(* Logix 5000 project; controller MyControlLogix 1756-L63 rev 13.1; software revision 13.04; part 2 of 4 *)
(* tags used below, declared in another part *)
   AFC56 : AFC;
(* MainProgram, continued *)

ROUTINE MainRoutine   (* ladder *)
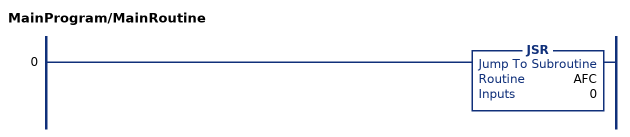
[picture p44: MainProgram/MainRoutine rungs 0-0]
   0: JSR(AFC,0);
END_ROUTINE

ROUTINE ModbusGateway_Block   (* ladder *)
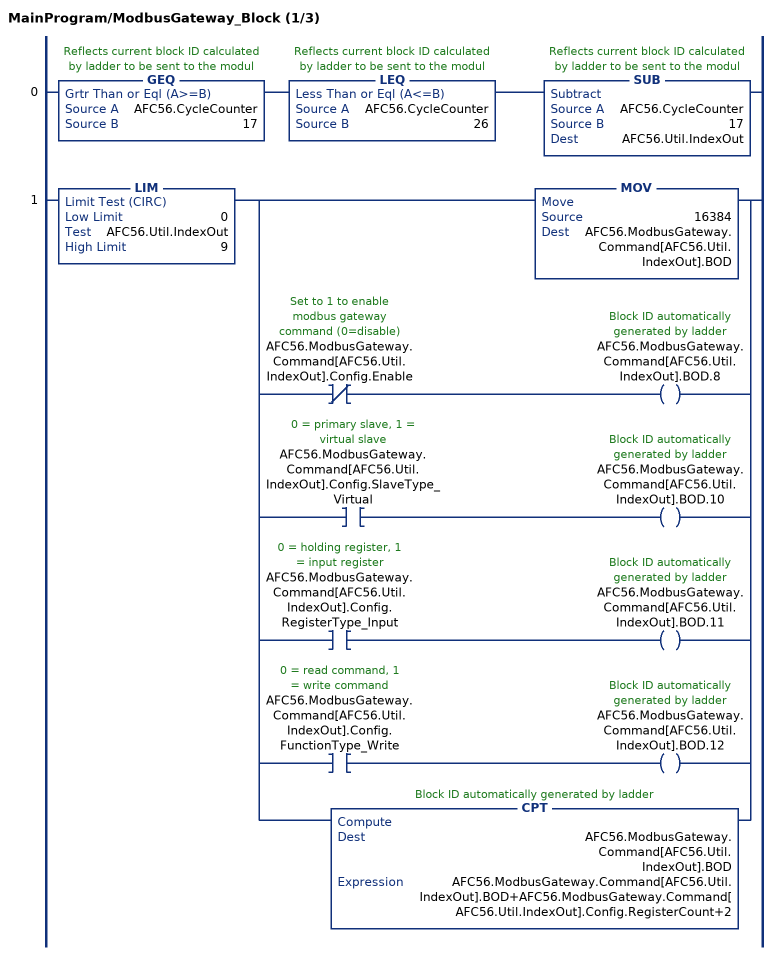
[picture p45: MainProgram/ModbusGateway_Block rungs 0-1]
   0: GEQ(AFC56.CycleCounter,17)LEQ(AFC56.CycleCounter,26)SUB(AFC56.CycleCounter,17,AFC56.Util.IndexOut);
   1: LIM(0,AFC56.Util.IndexOut,9)[MOV(16384,AFC56.ModbusGateway.Command[AFC56.Util.IndexOut].BOD) ,XIO(AFC56.ModbusGateway.Command[AFC56.Util.IndexOut].Config.Enable) OTE(AFC56.ModbusGateway.Command[AFC56.Util.IndexOut].BOD.8) ,XIC(AFC56.ModbusGateway.Command[AFC56.Util.IndexOut].Config.SlaveType_Virtual) OTE(AFC56.ModbusGateway.Command[AFC56.Util.IndexOut].BOD.10) ,XIC(AFC56.ModbusGateway.Command[AFC56.Util.IndexOut].Config.RegisterType_Input) OTE(AFC56.ModbusGateway.Command[AFC56.Util.IndexOut].BOD.11) ,XIC(AFC56.ModbusGateway.Command[AFC56.Util.IndexOut].Config.FunctionType_Write) OTE(AFC56.ModbusGateway.Command[AFC56.Util.IndexOut].BOD.12) ,CPT(AFC56.ModbusGateway.Command[AFC56.Util.IndexOut].BOD,AFC56.ModbusGateway.Command[AFC56.Util.IndexOut].BOD+AFC56.ModbusGateway.Command[AFC56.Util.IndexOut].Config.RegisterCount+2) ];
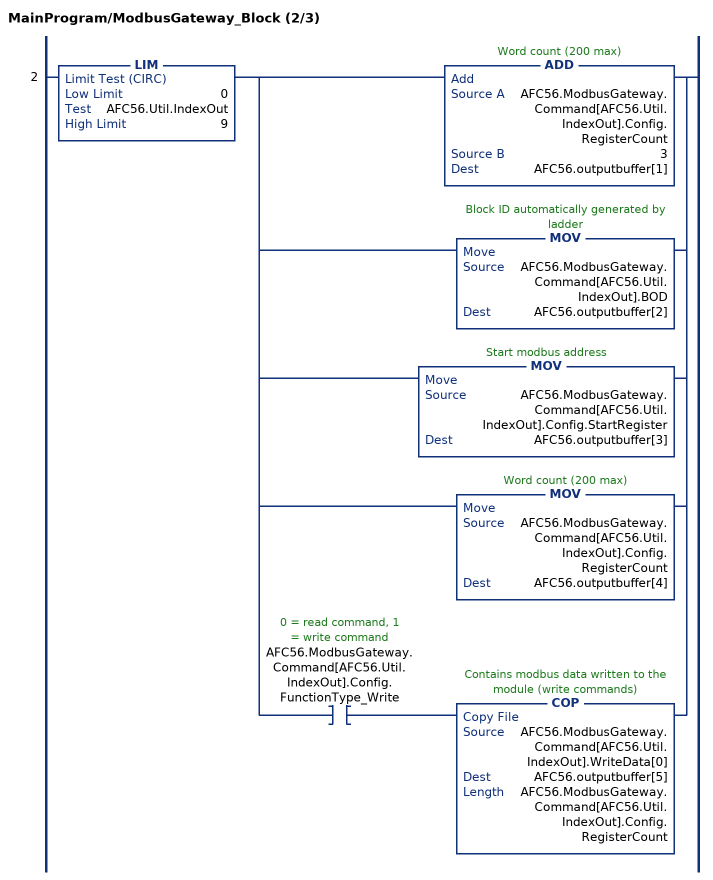
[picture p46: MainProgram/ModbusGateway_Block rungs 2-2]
   2: LIM(0,AFC56.Util.IndexOut,9)[ADD(AFC56.ModbusGateway.Command[AFC56.Util.IndexOut].Config.RegisterCount,3,AFC56.outputbuffer[1]) ,MOV(AFC56.ModbusGateway.Command[AFC56.Util.IndexOut].BOD,AFC56.outputbuffer[2]) ,MOV(AFC56.ModbusGateway.Command[AFC56.Util.IndexOut].Config.StartRegister,AFC56.outputbuffer[3]) ,MOV(AFC56.ModbusGateway.Command[AFC56.Util.IndexOut].Config.RegisterCount,AFC56.outputbuffer[4]) ,XIC(AFC56.ModbusGateway.Command[AFC56.Util.IndexOut].Config.FunctionType_Write) COP(AFC56.ModbusGateway.Command[AFC56.Util.IndexOut].WriteData[0],AFC56.outputbuffer[5],AFC56.ModbusGateway.Command[AFC56.Util.IndexOut].Config.RegisterCount) ];
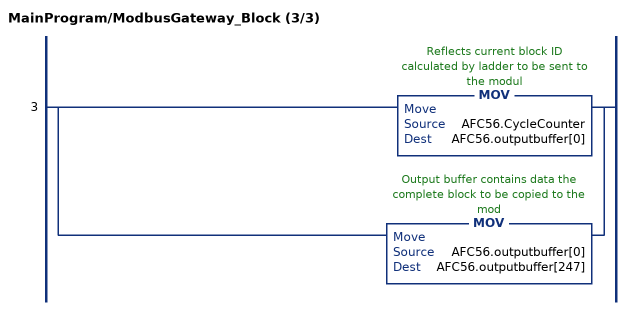
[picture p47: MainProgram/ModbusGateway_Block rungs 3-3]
   3: [MOV(AFC56.CycleCounter,AFC56.outputbuffer[0]) ,MOV(AFC56.outputbuffer[0],AFC56.outputbuffer[247]) ];
END_ROUTINE

ROUTINE ModbusMaster_Block   (* ladder *)
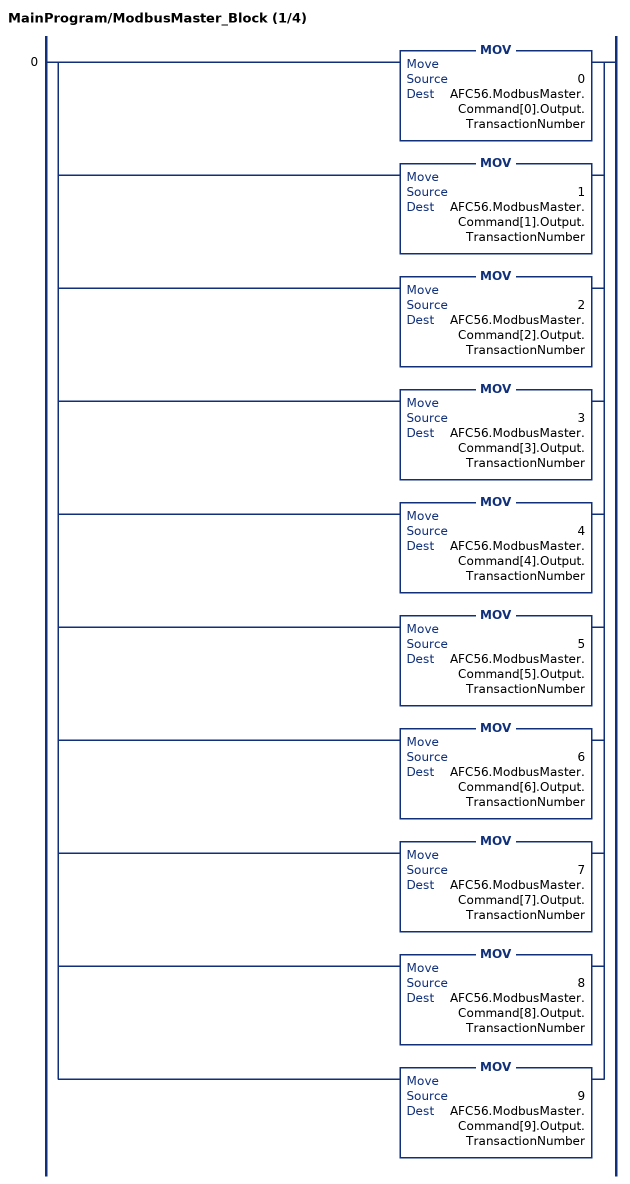
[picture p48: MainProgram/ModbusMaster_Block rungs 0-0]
   0: [MOV(0,AFC56.ModbusMaster.Command[0].Output.TransactionNumber) ,MOV(1,AFC56.ModbusMaster.Command[1].Output.TransactionNumber) ,MOV(2,AFC56.ModbusMaster.Command[2].Output.TransactionNumber) ,MOV(3,AFC56.ModbusMaster.Command[3].Output.TransactionNumber) ,MOV(4,AFC56.ModbusMaster.Command[4].Output.TransactionNumber) ,MOV(5,AFC56.ModbusMaster.Command[5].Output.TransactionNumber) ,MOV(6,AFC56.ModbusMaster.Command[6].Output.TransactionNumber) ,MOV(7,AFC56.ModbusMaster.Command[7].Output.TransactionNumber) ,MOV(8,AFC56.ModbusMaster.Command[8].Output.TransactionNumber) ,MOV(9,AFC56.ModbusMaster.Command[9].Output.TransactionNumber) ];
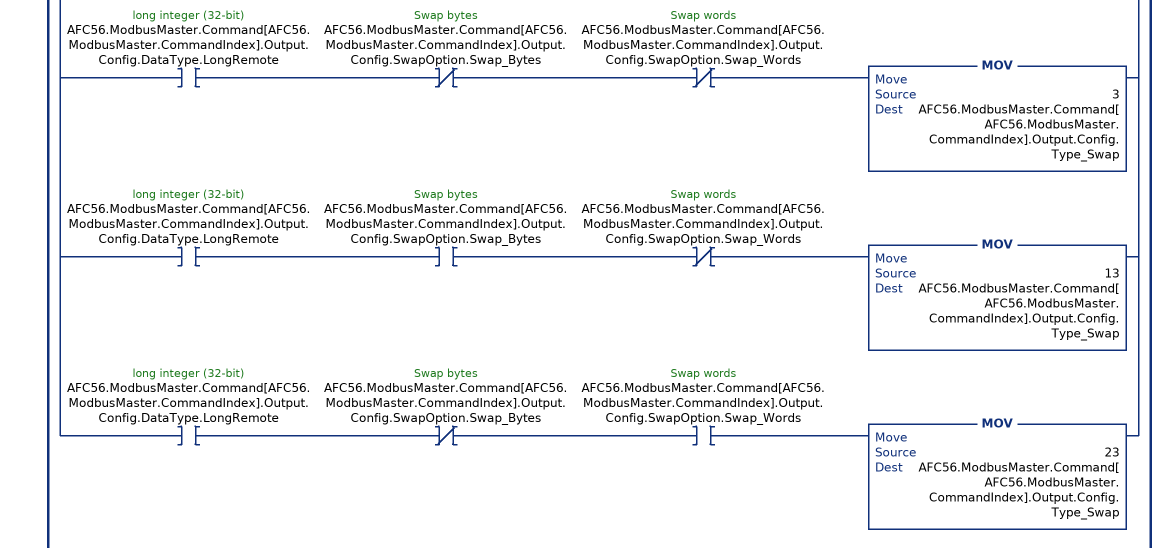
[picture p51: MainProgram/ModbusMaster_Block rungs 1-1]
   1: [[MOV(24576,AFC56.ModbusMaster.Command[AFC56.ModbusMaster.CommandIndex].Output.BOD) ,ADD(AFC56.ModbusMaster.Command[AFC56.ModbusMaster.CommandIndex].Output.BOD,130,AFC56.ModbusMaster.Command[AFC56.ModbusMaster.CommandIndex].Output.BOD) ] ,XIC(AFC56.ModbusMaster.Command[AFC56.ModbusMaster.CommandIndex].Output.Config.FunctionType_Write) OTE(AFC56.ModbusMaster.Command[AFC56.ModbusMaster.CommandIndex].Output.BOD.11) ,XIO(AFC56.ModbusMaster.Command[AFC56.ModbusMaster.CommandIndex].Output.Config.Enable) OTE(AFC56.ModbusMaster.Command[AFC56.ModbusMaster.CommandIndex].Output.BOD.8) ,XIC(AFC56.ModbusMaster.Command[AFC56.ModbusMaster.CommandIndex].Output.Config.RegisterBank_Input) OTE(AFC56.ModbusMaster.Command[AFC56.ModbusMaster.CommandIndex].Output.BOD.10) ,XIC(AFC56.ModbusMaster.Command[AFC56.ModbusMaster.CommandIndex].Output.Config.DataType.Bit) MOV(0,AFC56.ModbusMaster.Command[AFC56.ModbusMaster.CommandIndex].Output.Config.Type_Swap) ,XIC(AFC56.ModbusMaster.Command[AFC56.ModbusMaster.CommandIndex].Output.Config.DataType.Word) XIO(AFC56.ModbusMaster.Command[AFC56.ModbusMaster.CommandIndex].Output.Config.SwapOption.Swap_Bytes) MOV(1,AFC56.ModbusMaster.Command[AFC56.ModbusMaster.CommandIndex].Output.Config.Type_Swap) ,XIC(AFC56.ModbusMaster.Command[AFC56.ModbusMaster.CommandIndex].Output.Config.DataType.Word) XIC(AFC56.ModbusMaster.Command[AFC56.ModbusMaster.CommandIndex].Output.Config.SwapOption.Swap_Bytes) MOV(11,AFC56.ModbusMaster.Command[AFC56.ModbusMaster.CommandIndex].Output.Config.Type_Swap) ,XIC(AFC56.ModbusMaster.Command[AFC56.ModbusMaster.CommandIndex].Output.Config.DataType.Long) XIO(AFC56.ModbusMaster.Command[AFC56.ModbusMaster.CommandIndex].Output.Config.SwapOption.Swap_Bytes) XIO(AFC56.ModbusMaster.Command[AFC56.ModbusMaster.CommandIndex].Output.Config.SwapOption.Swap_Words) MOV(2,AFC56.ModbusMaster.Command[AFC56.ModbusMaster.CommandIndex].Output.Config.Type_Swap) ,XIC(AFC56.ModbusMaster.Command[AFC56.ModbusMaster.CommandIndex].Output.Config.DataType.Long) XIC(AFC56.ModbusMaster.Command[AFC56.ModbusMaster.CommandIndex].Output.Config.SwapOption.Swap_Bytes) XIO(AFC56.ModbusMaster.Command[AFC56.ModbusMaster.CommandIndex].Output.Config.SwapOption.Swap_Words) MOV(12,AFC56.ModbusMaster.Command[AFC56.ModbusMaster.CommandIndex].Output.Config.Type_Swap) ,XIC(AFC56.ModbusMaster.Command[AFC56.ModbusMaster.CommandIndex].Output.Config.DataType.Long) XIO(AFC56.ModbusMaster.Command[AFC56.ModbusMaster.CommandIndex].Output.Config.SwapOption.Swap_Bytes) XIC(AFC56.ModbusMaster.Command[AFC56.ModbusMaster.CommandIndex].Output.Config.SwapOption.Swap_Words) MOV(22,AFC56.ModbusMaster.Command[AFC56.ModbusMaster.CommandIndex].Output.Config.Type_Swap) ,XIC(AFC56.ModbusMaster.Command[AFC56.ModbusMaster.CommandIndex].Output.Config.DataType.LongRemote) XIO(AFC56.ModbusMaster.Command[AFC56.ModbusMaster.CommandIndex].Output.Config.SwapOption.Swap_Bytes) XIO(AFC56.ModbusMaster.Command[AFC56.ModbusMaster.CommandIndex].Output.Config.SwapOption.Swap_Words) MOV(3,AFC56.ModbusMaster.Command[AFC56.ModbusMaster.CommandIndex].Output.Config.Type_Swap) ,XIC(AFC56.ModbusMaster.Command[AFC56.ModbusMaster.CommandIndex].Output.Config.DataType.LongRemote) XIC(AFC56.ModbusMaster.Command[AFC56.ModbusMaster.CommandIndex].Output.Config.SwapOption.Swap_Bytes) XIO(AFC56.ModbusMaster.Command[AFC56.ModbusMaster.CommandIndex].Output.Config.SwapOption.Swap_Words) MOV(13,AFC56.ModbusMaster.Command[AFC56.ModbusMaster.CommandIndex].Output.Config.Type_Swap) ,XIC(AFC56.ModbusMaster.Command[AFC56.ModbusMaster.CommandIndex].Output.Config.DataType.LongRemote) XIO(AFC56.ModbusMaster.Command[AFC56.ModbusMaster.CommandIndex].Output.Config.SwapOption.Swap_Bytes) XIC(AFC56.ModbusMaster.Command[AFC56.ModbusMaster.CommandIndex].Output.Config.SwapOption.Swap_Words) MOV(23,AFC56.ModbusMaster.Command[AFC56.ModbusMaster.CommandIndex].Output.Config.Type_Swap) ];
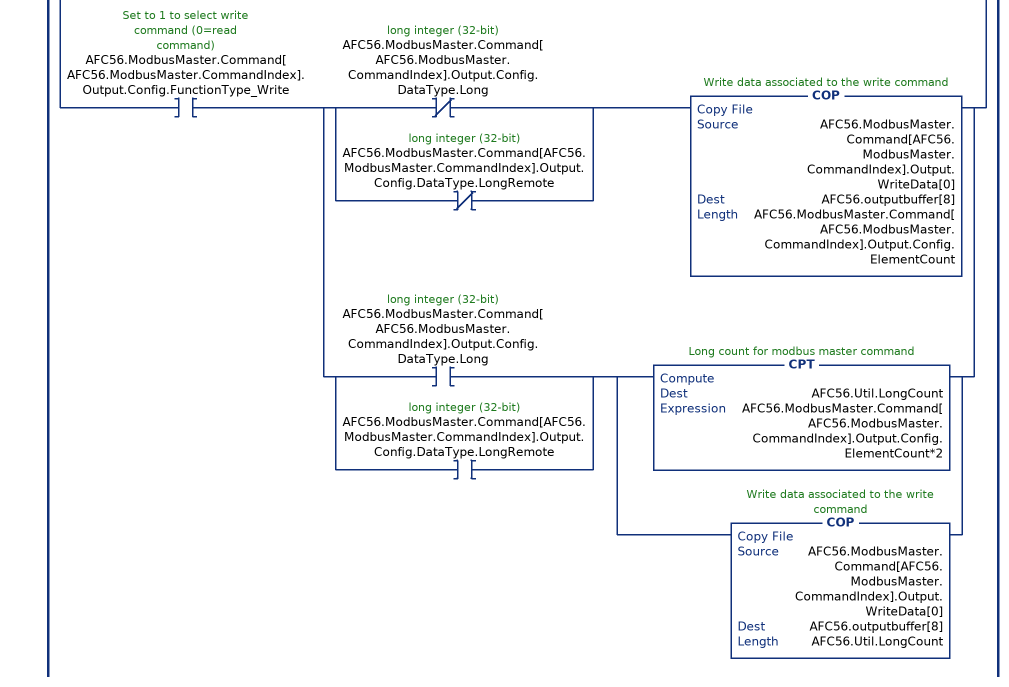
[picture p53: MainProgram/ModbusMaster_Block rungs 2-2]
   2: [MOV(131,AFC56.outputbuffer[1]) ,MOV(AFC56.ModbusMaster.Command[AFC56.ModbusMaster.CommandIndex].Output.BOD,AFC56.outputbuffer[2]) ,MOV(AFC56.ModbusMaster.Command[AFC56.ModbusMaster.CommandIndex].Output.TransactionNumber,AFC56.outputbuffer[3]) ,MOV(AFC56.ModbusMaster.Command[AFC56.ModbusMaster.CommandIndex].Output.Config.Type_Swap,AFC56.outputbuffer[4]) ,MOV(AFC56.ModbusMaster.Command[AFC56.ModbusMaster.CommandIndex].Output.Config.SlaveAddress,AFC56.outputbuffer[5]) ,MOV(AFC56.ModbusMaster.Command[AFC56.ModbusMaster.CommandIndex].Output.Config.ModbusAddress,AFC56.outputbuffer[6]) ,MOV(AFC56.ModbusMaster.Command[AFC56.ModbusMaster.CommandIndex].Output.Config.ElementCount,AFC56.outputbuffer[7]) ,XIC(AFC56.ModbusMaster.Command[AFC56.ModbusMaster.CommandIndex].Output.Config.FunctionType_Write) [[XIO(AFC56.ModbusMaster.Command[AFC56.ModbusMaster.CommandIndex].Output.Config.DataType.Long) ,XIO(AFC56.ModbusMaster.Command[AFC56.ModbusMaster.CommandIndex].Output.Config.DataType.LongRemote) ] COP(AFC56.ModbusMaster.Command[AFC56.ModbusMaster.CommandIndex].Output.WriteData[0],AFC56.outputbuffer[8],AFC56.ModbusMaster.Command[AFC56.ModbusMaster.CommandIndex].Output.Config.ElementCount) ,[XIC(AFC56.ModbusMaster.Command[AFC56.ModbusMaster.CommandIndex].Output.Config.DataType.Long) ,XIC(AFC56.ModbusMaster.Command[AFC56.ModbusMaster.CommandIndex].Output.Config.DataType.LongRemote) ] [CPT(AFC56.Util.LongCount,AFC56.ModbusMaster.Command[AFC56.ModbusMaster.CommandIndex].Output.Config.ElementCount*2) ,COP(AFC56.ModbusMaster.Command[AFC56.ModbusMaster.CommandIndex].Output.WriteData[0],AFC56.outputbuffer[8],AFC56.Util.LongCount) ] ] ];
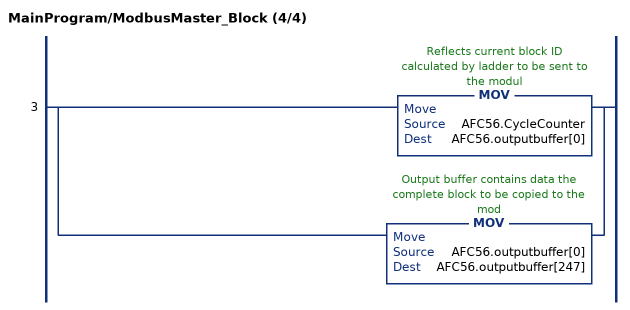
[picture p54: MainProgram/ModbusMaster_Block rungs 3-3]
   3: [MOV(AFC56.CycleCounter,AFC56.outputbuffer[0]) ,MOV(AFC56.outputbuffer[0],AFC56.outputbuffer[247]) ];
END_ROUTINE

ROUTINE ModbusPassThru_Block   (* ladder *)
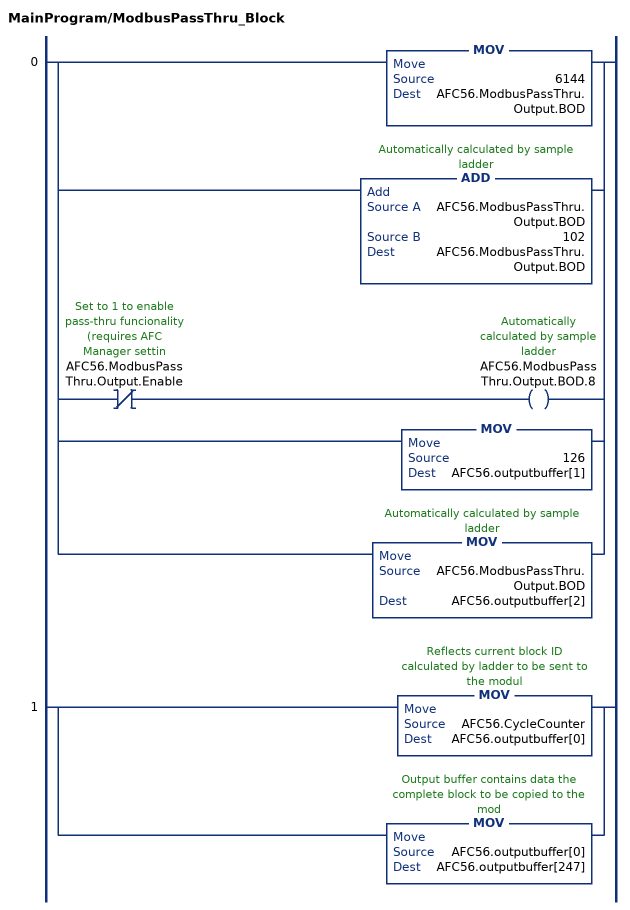
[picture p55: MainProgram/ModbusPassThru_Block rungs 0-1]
   0: [MOV(6144,AFC56.ModbusPassThru.Output.BOD) ,ADD(AFC56.ModbusPassThru.Output.BOD,102,AFC56.ModbusPassThru.Output.BOD) ,XIO(AFC56.ModbusPassThru.Output.Enable) OTE(AFC56.ModbusPassThru.Output.BOD.8) ,MOV(126,AFC56.outputbuffer[1]) ,MOV(AFC56.ModbusPassThru.Output.BOD,AFC56.outputbuffer[2]) ];
   1: [MOV(AFC56.CycleCounter,AFC56.outputbuffer[0]) ,MOV(AFC56.outputbuffer[0],AFC56.outputbuffer[247]) ];
END_ROUTINE

ROUTINE Plc_Set_Clock   (* ladder *)
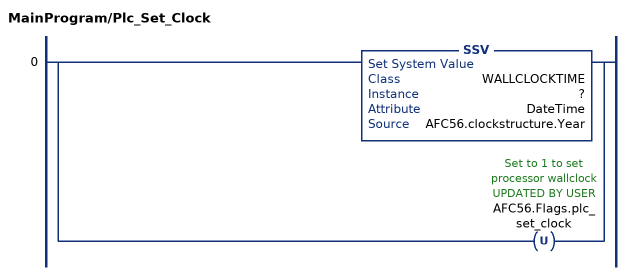
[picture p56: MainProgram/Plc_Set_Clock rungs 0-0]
   0: [SSV(WALLCLOCKTIME,?,DateTime,AFC56.clockstructure.Year) ,OTU(AFC56.Flags.plc_set_clock) ];
END_ROUTINE

ROUTINE Process_Block   (* ladder *)
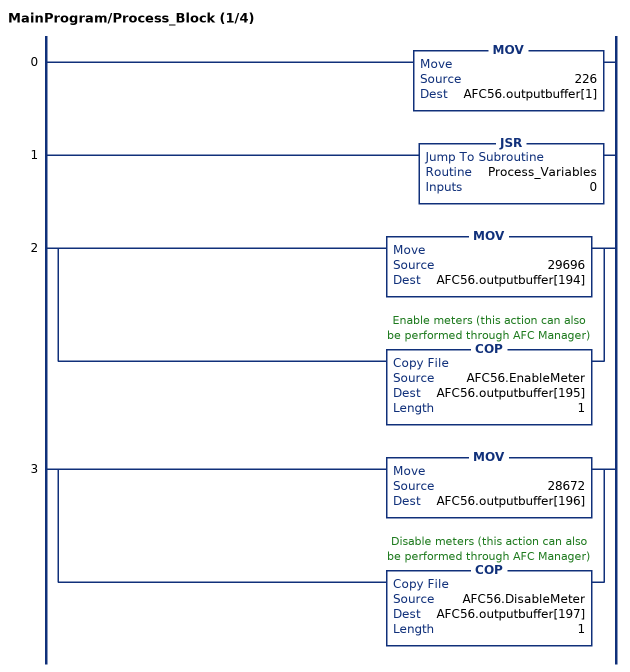
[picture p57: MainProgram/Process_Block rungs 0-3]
   0: MOV(226,AFC56.outputbuffer[1]);
   1: JSR(Process_Variables,0);
   2: [MOV(29696,AFC56.outputbuffer[194]) ,COP(AFC56.EnableMeter,AFC56.outputbuffer[195],1) ];
   3: [MOV(28672,AFC56.outputbuffer[196]) ,COP(AFC56.DisableMeter,AFC56.outputbuffer[197],1) ];
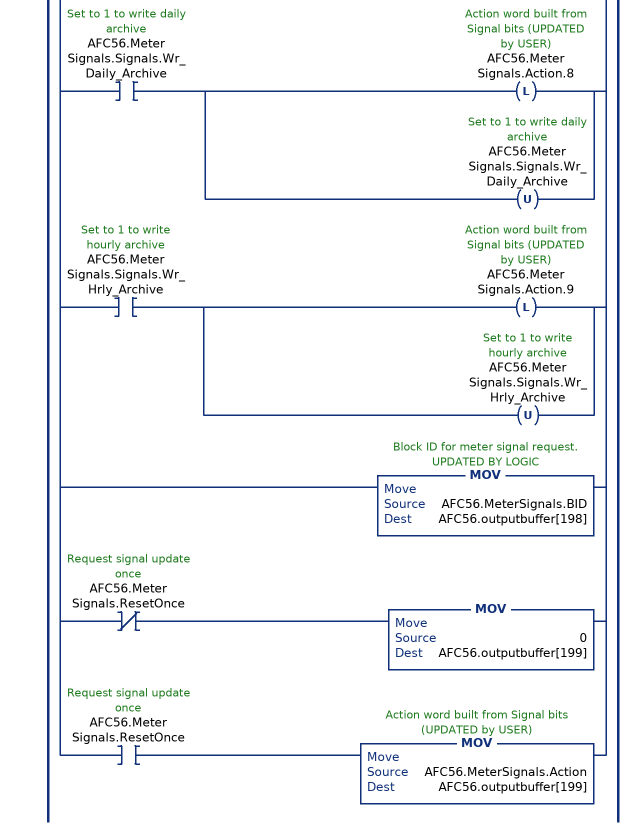
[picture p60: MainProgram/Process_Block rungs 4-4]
   4: [ADD(12288,AFC56.MeterSignals.Meter,AFC56.MeterSignals.BID) ,XIO(AFC56.MeterSignals.Enable) OTE(AFC56.MeterSignals.BID.8) ,XIC(AFC56.MeterSignals.Signals.Sel_Stream1) [OTL(AFC56.MeterSignals.Action.0) ,OTU(AFC56.MeterSignals.Signals.Sel_Stream1) ] ,XIC(AFC56.MeterSignals.Signals.Sel_Stream2) [OTL(AFC56.MeterSignals.Action.1) ,OTU(AFC56.MeterSignals.Signals.Sel_Stream2) ] ,XIC(AFC56.MeterSignals.Signals.Sel_Stream3) [OTL(AFC56.MeterSignals.Action.2) ,OTU(AFC56.MeterSignals.Signals.Sel_Stream3) ] ,XIC(AFC56.MeterSignals.Signals.Sel_Stream4) [OTL(AFC56.MeterSignals.Action.3) ,OTU(AFC56.MeterSignals.Signals.Sel_Stream4) ] ,XIC(AFC56.MeterSignals.Signals.Res_Acc1) [OTL(AFC56.MeterSignals.Action.4) ,OTU(AFC56.MeterSignals.Signals.Res_Acc1) ] ,XIC(AFC56.MeterSignals.Signals.Res_Acc2) [OTL(AFC56.MeterSignals.Action.5) ,OTU(AFC56.MeterSignals.Signals.Res_Acc2) ] ,XIC(AFC56.MeterSignals.Signals.Res_Acc3) [OTL(AFC56.MeterSignals.Action.6) ,OTU(AFC56.MeterSignals.Signals.Res_Acc3) ] ,XIC(AFC56.MeterSignals.Signals.Res_Acc4) [OTL(AFC56.MeterSignals.Action.7) ,OTU(AFC56.MeterSignals.Signals.Res_Acc4) ] ,XIC(AFC56.MeterSignals.Signals.Wr_Daily_Archive) [OTL(AFC56.MeterSignals.Action.8) ,OTU(AFC56.MeterSignals.Signals.Wr_Daily_Archive) ] ,XIC(AFC56.MeterSignals.Signals.Wr_Hrly_Archive) [OTL(AFC56.MeterSignals.Action.9) ,OTU(AFC56.MeterSignals.Signals.Wr_Hrly_Archive) ] ,MOV(AFC56.MeterSignals.BID,AFC56.outputbuffer[198]) ,XIO(AFC56.MeterSignals.ResetOnce) MOV(0,AFC56.outputbuffer[199]) ,XIC(AFC56.MeterSignals.ResetOnce) MOV(AFC56.MeterSignals.Action,AFC56.outputbuffer[199]) ];
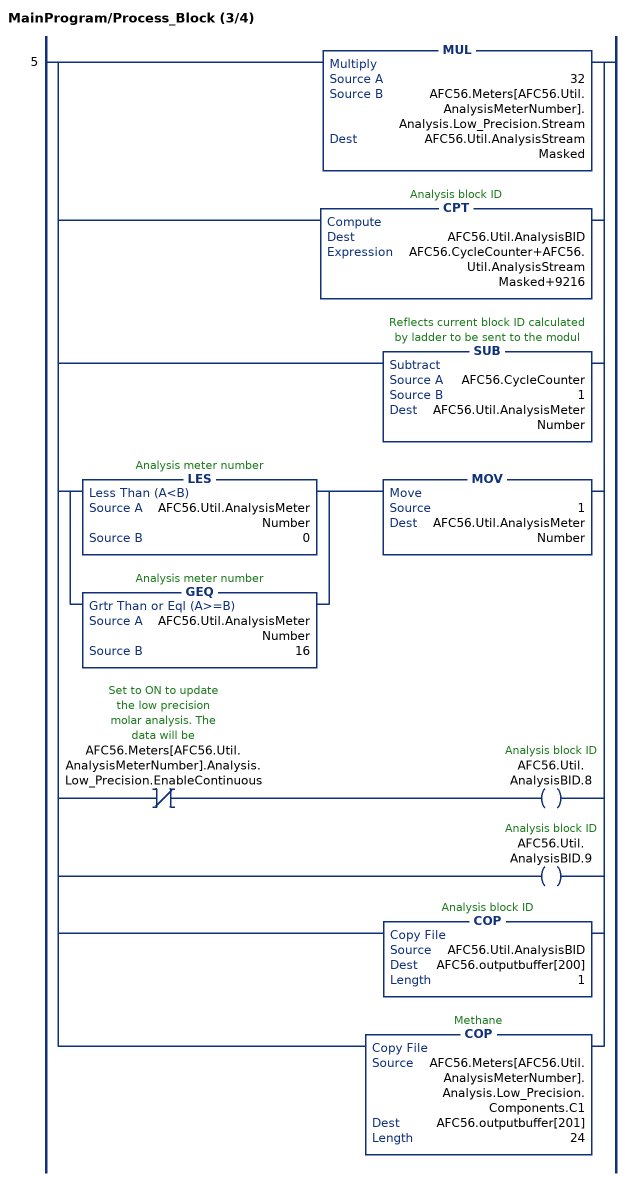
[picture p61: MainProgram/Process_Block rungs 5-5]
   5: [MUL(32,AFC56.Meters[AFC56.Util.AnalysisMeterNumber].Analysis.Low_Precision.Stream,AFC56.Util.AnalysisStreamMasked) ,CPT(AFC56.Util.AnalysisBID,AFC56.CycleCounter+AFC56.Util.AnalysisStreamMasked+9216) ,SUB(AFC56.CycleCounter,1,AFC56.Util.AnalysisMeterNumber) ,[LES(AFC56.Util.AnalysisMeterNumber,0) ,GEQ(AFC56.Util.AnalysisMeterNumber,16) ] MOV(1,AFC56.Util.AnalysisMeterNumber) ,XIO(AFC56.Meters[AFC56.Util.AnalysisMeterNumber].Analysis.Low_Precision.EnableContinuous) OTE(AFC56.Util.AnalysisBID.8) ,OTE(AFC56.Util.AnalysisBID.9) ,COP(AFC56.Util.AnalysisBID,AFC56.outputbuffer[200],1) ,COP(AFC56.Meters[AFC56.Util.AnalysisMeterNumber].Analysis.Low_Precision.Components.C1,AFC56.outputbuffer[201],24) ];
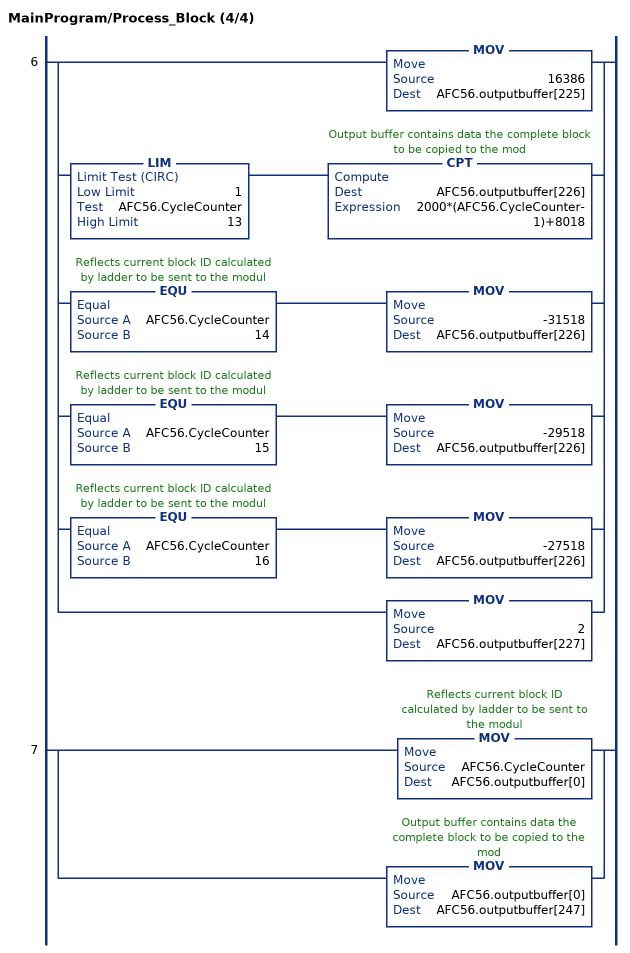
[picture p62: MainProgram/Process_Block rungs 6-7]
   6: [MOV(16386,AFC56.outputbuffer[225]) ,LIM(1,AFC56.CycleCounter,13) CPT(AFC56.outputbuffer[226],2000*(AFC56.CycleCounter-1)+8018) ,EQU(AFC56.CycleCounter,14) MOV(-31518,AFC56.outputbuffer[226]) ,EQU(AFC56.CycleCounter,15) MOV(-29518,AFC56.outputbuffer[226]) ,EQU(AFC56.CycleCounter,16) MOV(-27518,AFC56.outputbuffer[226]) ,MOV(2,AFC56.outputbuffer[227]) ];
   7: [MOV(AFC56.CycleCounter,AFC56.outputbuffer[0]) ,MOV(AFC56.outputbuffer[0],AFC56.outputbuffer[247]) ];
END_ROUTINE

ROUTINE Process_Results   (* ladder *)
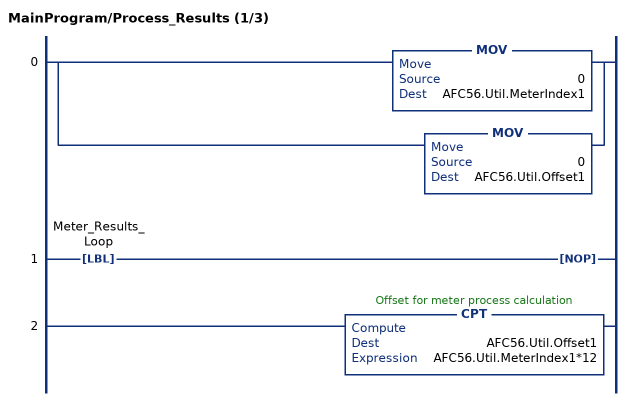
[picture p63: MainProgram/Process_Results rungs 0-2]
   0: [MOV(0,AFC56.Util.MeterIndex1) ,MOV(0,AFC56.Util.Offset1) ];
   1: LBL(Meter_Results_Loop)NOP();
   2: CPT(AFC56.Util.Offset1,AFC56.Util.MeterIndex1*12);
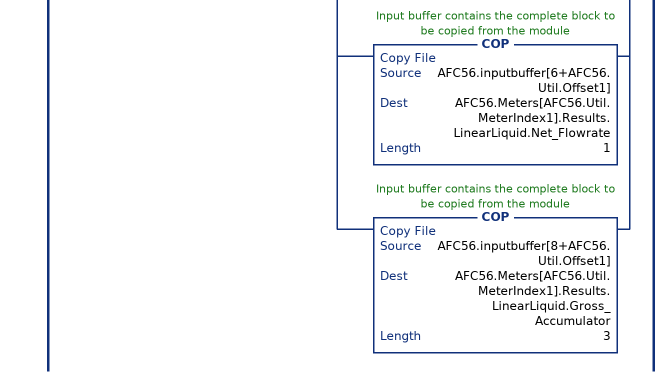
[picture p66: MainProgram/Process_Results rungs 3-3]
   3: [MOV(AFC56.inputbuffer[2+AFC56.Util.Offset1],AFC56.Meters[AFC56.Util.MeterIndex1].Results.BID) ,MOV(AFC56.inputbuffer[3+AFC56.Util.Offset1],AFC56.Meters[AFC56.Util.MeterIndex1].Results.Alarms) ,XIO(AFC56.Meters[AFC56.Util.MeterIndex1].Profile.MeterType) XIO(AFC56.Meters[AFC56.Util.MeterIndex1].Profile.ProductGroup) [COP(AFC56.inputbuffer[4+AFC56.Util.Offset1],AFC56.Meters[AFC56.Util.MeterIndex1].Results.DifferentialGas.Net_Accumulator,1) ,COP(AFC56.inputbuffer[6+AFC56.Util.Offset1],AFC56.Meters[AFC56.Util.MeterIndex1].Results.DifferentialGas.Net_Flowrate,4) ] ,XIO(AFC56.Meters[AFC56.Util.MeterIndex1].Profile.MeterType) XIC(AFC56.Meters[AFC56.Util.MeterIndex1].Profile.ProductGroup) [COP(AFC56.inputbuffer[4+AFC56.Util.Offset1],AFC56.Meters[AFC56.Util.MeterIndex1].Results.DifferentialLiquid.Net_Accumulator,1) ,COP(AFC56.inputbuffer[6+AFC56.Util.Offset1],AFC56.Meters[AFC56.Util.MeterIndex1].Results.DifferentialLiquid.Net_Flowrate,1) ,COP(AFC56.inputbuffer[8+AFC56.Util.Offset1],AFC56.Meters[AFC56.Util.MeterIndex1].Results.DifferentialLiquid.Gross_Accumulator,3) ] ,XIC(AFC56.Meters[AFC56.Util.MeterIndex1].Profile.MeterType) XIO(AFC56.Meters[AFC56.Util.MeterIndex1].Profile.ProductGroup) [COP(AFC56.inputbuffer[4+AFC56.Util.Offset1],AFC56.Meters[AFC56.Util.MeterIndex1].Results.LinearGas.Net_Accumulator,1) ,COP(AFC56.inputbuffer[6+AFC56.Util.Offset1],AFC56.Meters[AFC56.Util.MeterIndex1].Results.LinearGas.Net_Flowrate,4) ] ,XIC(AFC56.Meters[AFC56.Util.MeterIndex1].Profile.MeterType) XIC(AFC56.Meters[AFC56.Util.MeterIndex1].Profile.ProductGroup) [COP(AFC56.inputbuffer[4+AFC56.Util.Offset1],AFC56.Meters[AFC56.Util.MeterIndex1].Results.LinearLiquid.Net_Accumulator,1) ,COP(AFC56.inputbuffer[6+AFC56.Util.Offset1],AFC56.Meters[AFC56.Util.MeterIndex1].Results.LinearLiquid.Net_Flowrate,1) ,COP(AFC56.inputbuffer[8+AFC56.Util.Offset1],AFC56.Meters[AFC56.Util.MeterIndex1].Results.LinearLiquid.Gross_Accumulator,3) ] ];
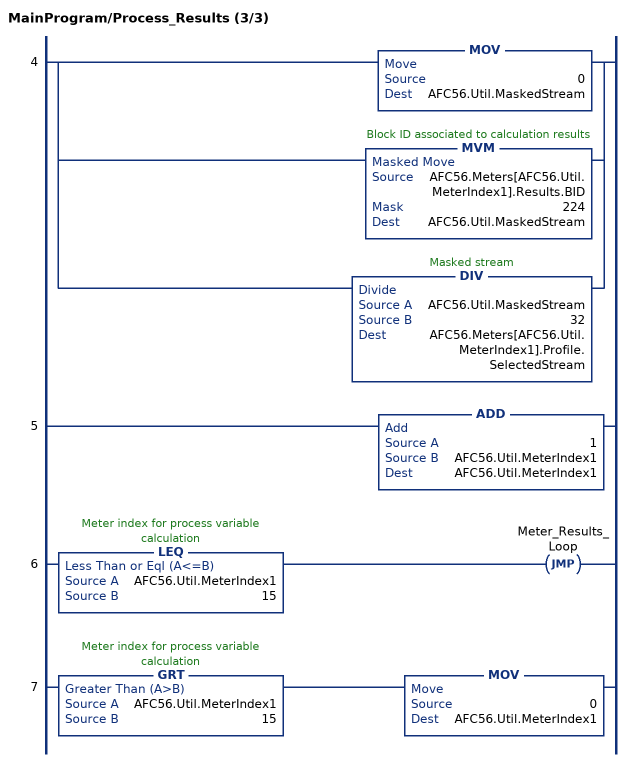
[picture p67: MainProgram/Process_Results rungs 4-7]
   4: [MOV(0,AFC56.Util.MaskedStream) ,MVM(AFC56.Meters[AFC56.Util.MeterIndex1].Results.BID,224,AFC56.Util.MaskedStream) ,DIV(AFC56.Util.MaskedStream,32,AFC56.Meters[AFC56.Util.MeterIndex1].Profile.SelectedStream) ];
   5: ADD(1,AFC56.Util.MeterIndex1,AFC56.Util.MeterIndex1);
   6: LEQ(AFC56.Util.MeterIndex1,15)JMP(Meter_Results_Loop);
   7: GRT(AFC56.Util.MeterIndex1,15)MOV(0,AFC56.Util.MeterIndex1);
END_ROUTINE

ROUTINE Process_Variables   (* ladder *)
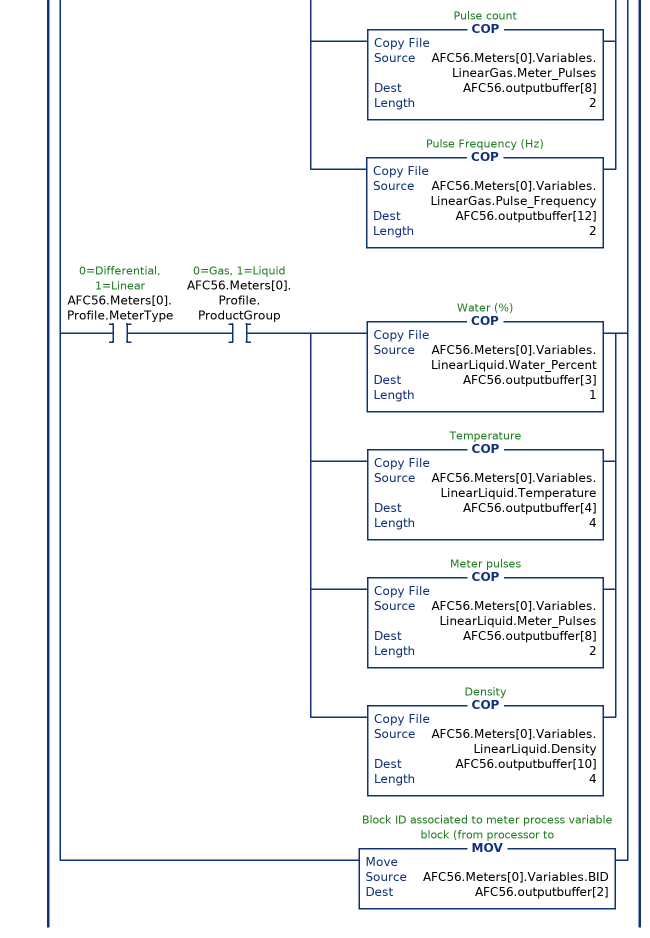
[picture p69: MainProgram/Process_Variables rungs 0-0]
   0: [ADD(1,8192,AFC56.Meters[0].Variables.BID) ,XIO(AFC56.EnableStatus.Meter1) [OTE(AFC56.Meters[0].Variables.BID.8) ,OTU(AFC56.DisableMeter.Meter1) ] ,XIC(AFC56.EnableStatus.Meter1) OTU(AFC56.EnableMeter.Meter1) ,XIO(AFC56.Meters[0].Profile.MeterType) XIO(AFC56.Meters[0].Profile.ProductGroup) COP(AFC56.Meters[0].Variables.DifferentialGas.Temperature,AFC56.outputbuffer[4],6) ,XIO(AFC56.Meters[0].Profile.MeterType) XIC(AFC56.Meters[0].Profile.ProductGroup) [COP(AFC56.Meters[0].Variables.DifferentialLiquid.Water_Percent,AFC56.outputbuffer[3],1) ,COP(AFC56.Meters[0].Variables.DifferentialLiquid.Temperature,AFC56.outputbuffer[4],8) ] ,XIC(AFC56.Meters[0].Profile.MeterType) XIO(AFC56.Meters[0].Profile.ProductGroup) [COP(AFC56.Meters[0].Variables.LinearGas.Temperature,AFC56.outputbuffer[4],4) ,COP(AFC56.Meters[0].Variables.LinearGas.Meter_Pulses,AFC56.outputbuffer[8],2) ,COP(AFC56.Meters[0].Variables.LinearGas.Pulse_Frequency,AFC56.outputbuffer[12],2) ] ,XIC(AFC56.Meters[0].Profile.MeterType) XIC(AFC56.Meters[0].Profile.ProductGroup) [COP(AFC56.Meters[0].Variables.LinearLiquid.Water_Percent,AFC56.outputbuffer[3],1) ,COP(AFC56.Meters[0].Variables.LinearLiquid.Temperature,AFC56.outputbuffer[4],4) ,COP(AFC56.Meters[0].Variables.LinearLiquid.Meter_Pulses,AFC56.outputbuffer[8],2) ,COP(AFC56.Meters[0].Variables.LinearLiquid.Density,AFC56.outputbuffer[10],4) ] ,MOV(AFC56.Meters[0].Variables.BID,AFC56.outputbuffer[2]) ];
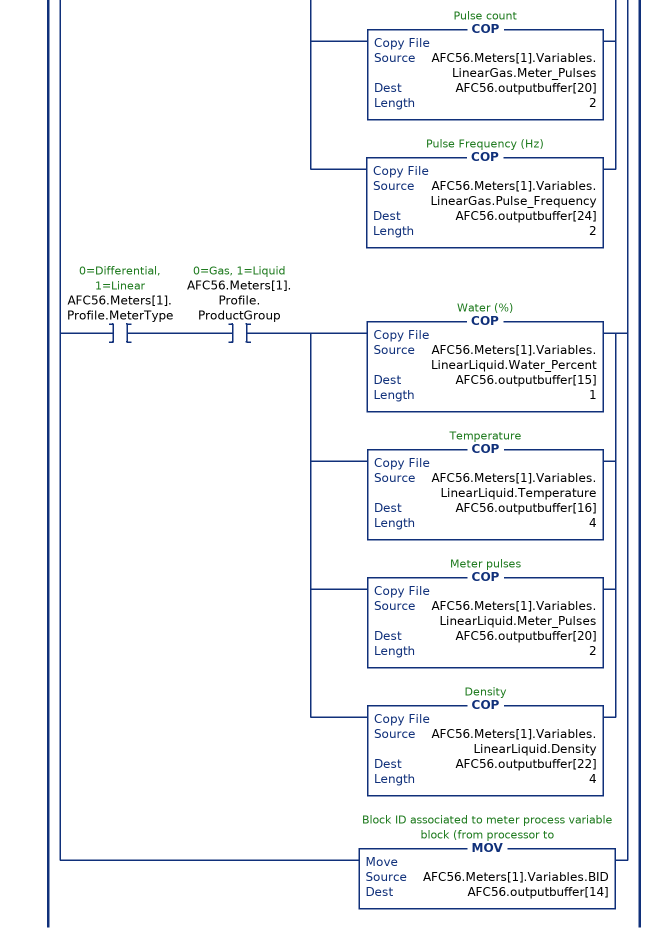
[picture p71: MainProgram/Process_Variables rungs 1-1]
   1: [ADD(2,8192,AFC56.Meters[1].Variables.BID) ,XIO(AFC56.EnableStatus.Meter2) [OTE(AFC56.Meters[1].Variables.BID.8) ,OTU(AFC56.DisableMeter.Meter2) ] ,XIC(AFC56.EnableStatus.Meter2) OTU(AFC56.EnableMeter.Meter2) ,XIO(AFC56.Meters[1].Profile.MeterType) XIO(AFC56.Meters[1].Profile.ProductGroup) COP(AFC56.Meters[1].Variables.DifferentialGas.Temperature,AFC56.outputbuffer[16],6) ,XIO(AFC56.Meters[1].Profile.MeterType) XIC(AFC56.Meters[1].Profile.ProductGroup) [COP(AFC56.Meters[1].Variables.DifferentialLiquid.Water_Percent,AFC56.outputbuffer[15],1) ,COP(AFC56.Meters[1].Variables.DifferentialLiquid.Temperature,AFC56.outputbuffer[16],8) ] ,XIC(AFC56.Meters[1].Profile.MeterType) XIO(AFC56.Meters[1].Profile.ProductGroup) [COP(AFC56.Meters[1].Variables.LinearGas.Temperature,AFC56.outputbuffer[16],4) ,COP(AFC56.Meters[1].Variables.LinearGas.Meter_Pulses,AFC56.outputbuffer[20],2) ,COP(AFC56.Meters[1].Variables.LinearGas.Pulse_Frequency,AFC56.outputbuffer[24],2) ] ,XIC(AFC56.Meters[1].Profile.MeterType) XIC(AFC56.Meters[1].Profile.ProductGroup) [COP(AFC56.Meters[1].Variables.LinearLiquid.Water_Percent,AFC56.outputbuffer[15],1) ,COP(AFC56.Meters[1].Variables.LinearLiquid.Temperature,AFC56.outputbuffer[16],4) ,COP(AFC56.Meters[1].Variables.LinearLiquid.Meter_Pulses,AFC56.outputbuffer[20],2) ,COP(AFC56.Meters[1].Variables.LinearLiquid.Density,AFC56.outputbuffer[22],4) ] ,MOV(AFC56.Meters[1].Variables.BID,AFC56.outputbuffer[14]) ];
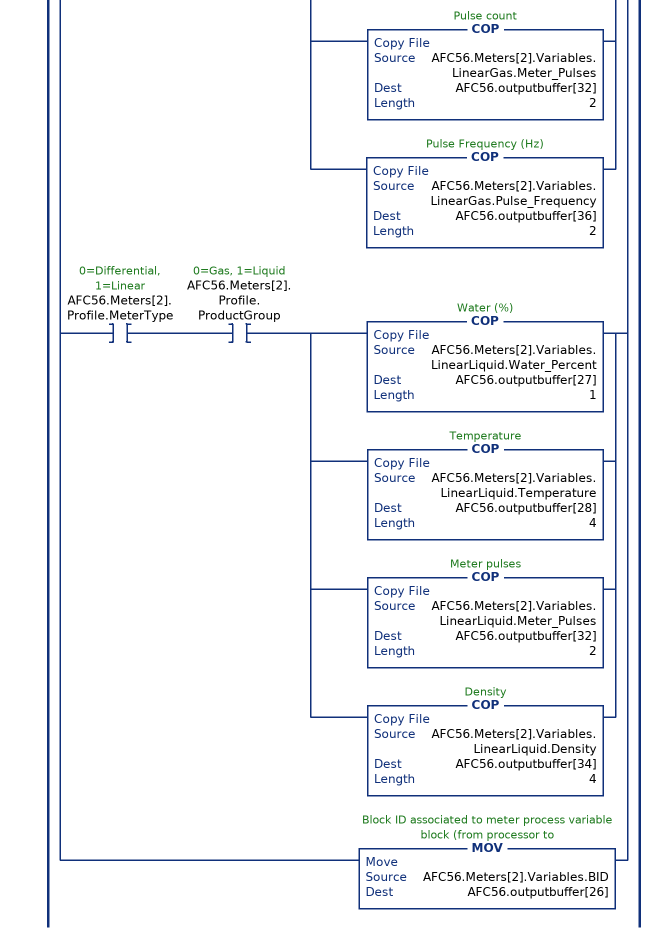
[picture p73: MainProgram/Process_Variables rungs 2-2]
   2: [ADD(3,8192,AFC56.Meters[2].Variables.BID) ,XIO(AFC56.EnableStatus.Meter3) [OTE(AFC56.Meters[2].Variables.BID.8) ,OTU(AFC56.DisableMeter.Meter3) ] ,XIC(AFC56.EnableStatus.Meter3) OTU(AFC56.EnableMeter.Meter3) ,XIO(AFC56.Meters[2].Profile.MeterType) XIO(AFC56.Meters[2].Profile.ProductGroup) COP(AFC56.Meters[2].Variables.DifferentialGas.Temperature,AFC56.outputbuffer[28],6) ,XIO(AFC56.Meters[2].Profile.MeterType) XIC(AFC56.Meters[2].Profile.ProductGroup) [COP(AFC56.Meters[2].Variables.DifferentialLiquid.Water_Percent,AFC56.outputbuffer[27],1) ,COP(AFC56.Meters[2].Variables.DifferentialLiquid.Temperature,AFC56.outputbuffer[28],8) ] ,XIC(AFC56.Meters[2].Profile.MeterType) XIO(AFC56.Meters[2].Profile.ProductGroup) [COP(AFC56.Meters[2].Variables.LinearGas.Temperature,AFC56.outputbuffer[28],4) ,COP(AFC56.Meters[2].Variables.LinearGas.Meter_Pulses,AFC56.outputbuffer[32],2) ,COP(AFC56.Meters[2].Variables.LinearGas.Pulse_Frequency,AFC56.outputbuffer[36],2) ] ,XIC(AFC56.Meters[2].Profile.MeterType) XIC(AFC56.Meters[2].Profile.ProductGroup) [COP(AFC56.Meters[2].Variables.LinearLiquid.Water_Percent,AFC56.outputbuffer[27],1) ,COP(AFC56.Meters[2].Variables.LinearLiquid.Temperature,AFC56.outputbuffer[28],4) ,COP(AFC56.Meters[2].Variables.LinearLiquid.Meter_Pulses,AFC56.outputbuffer[32],2) ,COP(AFC56.Meters[2].Variables.LinearLiquid.Density,AFC56.outputbuffer[34],4) ] ,MOV(AFC56.Meters[2].Variables.BID,AFC56.outputbuffer[26]) ];
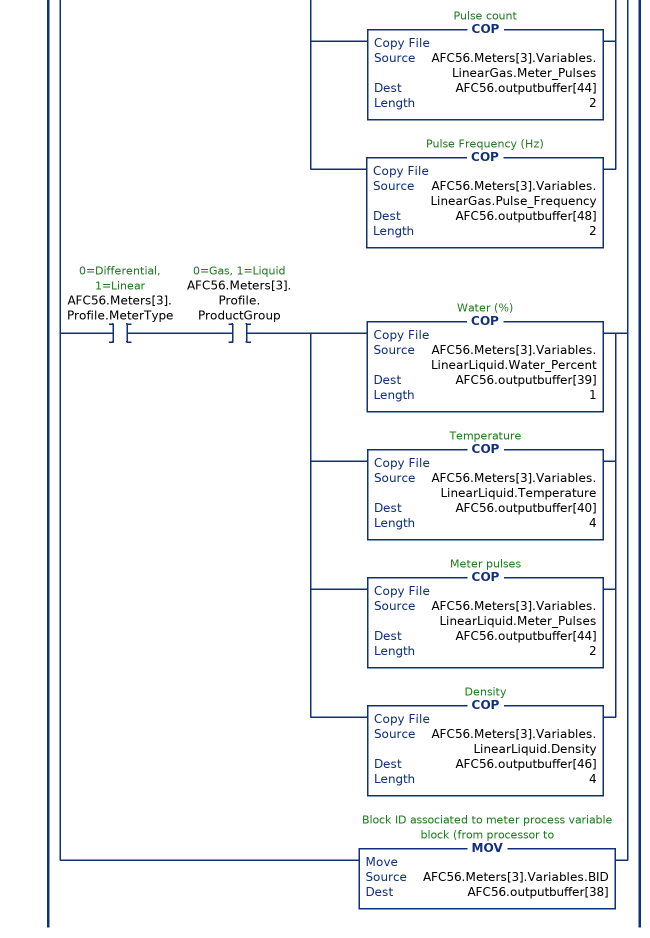
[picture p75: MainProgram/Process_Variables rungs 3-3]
   3: [ADD(4,8192,AFC56.Meters[3].Variables.BID) ,XIO(AFC56.EnableStatus.Meter4) [OTE(AFC56.Meters[3].Variables.BID.8) ,OTU(AFC56.DisableMeter.Meter4) ] ,XIC(AFC56.EnableStatus.Meter4) OTU(AFC56.EnableMeter.Meter4) ,XIO(AFC56.Meters[3].Profile.MeterType) XIO(AFC56.Meters[3].Profile.ProductGroup) COP(AFC56.Meters[3].Variables.DifferentialGas.Temperature,AFC56.outputbuffer[40],6) ,XIO(AFC56.Meters[3].Profile.MeterType) XIC(AFC56.Meters[3].Profile.ProductGroup) [COP(AFC56.Meters[3].Variables.DifferentialLiquid.Water_Percent,AFC56.outputbuffer[39],1) ,COP(AFC56.Meters[3].Variables.DifferentialLiquid.Temperature,AFC56.outputbuffer[40],8) ] ,XIC(AFC56.Meters[3].Profile.MeterType) XIO(AFC56.Meters[3].Profile.ProductGroup) [COP(AFC56.Meters[3].Variables.LinearGas.Temperature,AFC56.outputbuffer[40],4) ,COP(AFC56.Meters[3].Variables.LinearGas.Meter_Pulses,AFC56.outputbuffer[44],2) ,COP(AFC56.Meters[3].Variables.LinearGas.Pulse_Frequency,AFC56.outputbuffer[48],2) ] ,XIC(AFC56.Meters[3].Profile.MeterType) XIC(AFC56.Meters[3].Profile.ProductGroup) [COP(AFC56.Meters[3].Variables.LinearLiquid.Water_Percent,AFC56.outputbuffer[39],1) ,COP(AFC56.Meters[3].Variables.LinearLiquid.Temperature,AFC56.outputbuffer[40],4) ,COP(AFC56.Meters[3].Variables.LinearLiquid.Meter_Pulses,AFC56.outputbuffer[44],2) ,COP(AFC56.Meters[3].Variables.LinearLiquid.Density,AFC56.outputbuffer[46],4) ] ,MOV(AFC56.Meters[3].Variables.BID,AFC56.outputbuffer[38]) ];
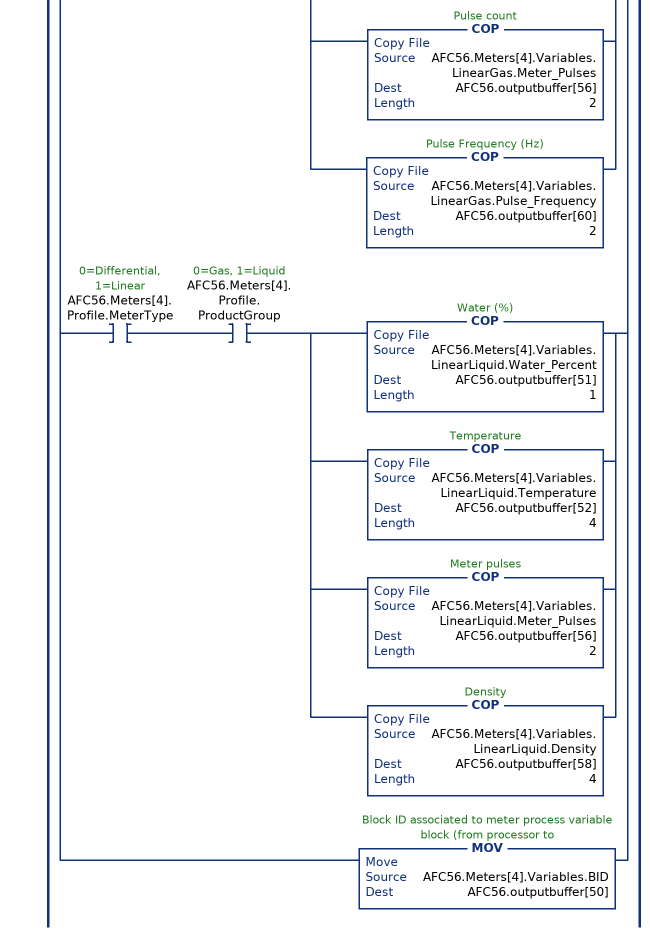
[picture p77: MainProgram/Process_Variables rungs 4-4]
   4: [ADD(5,8192,AFC56.Meters[4].Variables.BID) ,XIO(AFC56.EnableStatus.Meter5) [OTE(AFC56.Meters[4].Variables.BID.8) ,OTU(AFC56.DisableMeter.Meter5) ] ,XIC(AFC56.EnableStatus.Meter5) OTU(AFC56.EnableMeter.Meter5) ,XIO(AFC56.Meters[4].Profile.MeterType) XIO(AFC56.Meters[4].Profile.ProductGroup) COP(AFC56.Meters[4].Variables.DifferentialGas.Temperature,AFC56.outputbuffer[52],6) ,XIO(AFC56.Meters[4].Profile.MeterType) XIC(AFC56.Meters[4].Profile.ProductGroup) [COP(AFC56.Meters[4].Variables.DifferentialLiquid.Water_Percent,AFC56.outputbuffer[51],1) ,COP(AFC56.Meters[4].Variables.DifferentialLiquid.Temperature,AFC56.outputbuffer[52],8) ] ,XIC(AFC56.Meters[4].Profile.MeterType) XIO(AFC56.Meters[4].Profile.ProductGroup) [COP(AFC56.Meters[4].Variables.LinearGas.Temperature,AFC56.outputbuffer[52],4) ,COP(AFC56.Meters[4].Variables.LinearGas.Meter_Pulses,AFC56.outputbuffer[56],2) ,COP(AFC56.Meters[4].Variables.LinearGas.Pulse_Frequency,AFC56.outputbuffer[60],2) ] ,XIC(AFC56.Meters[4].Profile.MeterType) XIC(AFC56.Meters[4].Profile.ProductGroup) [COP(AFC56.Meters[4].Variables.LinearLiquid.Water_Percent,AFC56.outputbuffer[51],1) ,COP(AFC56.Meters[4].Variables.LinearLiquid.Temperature,AFC56.outputbuffer[52],4) ,COP(AFC56.Meters[4].Variables.LinearLiquid.Meter_Pulses,AFC56.outputbuffer[56],2) ,COP(AFC56.Meters[4].Variables.LinearLiquid.Density,AFC56.outputbuffer[58],4) ] ,MOV(AFC56.Meters[4].Variables.BID,AFC56.outputbuffer[50]) ];
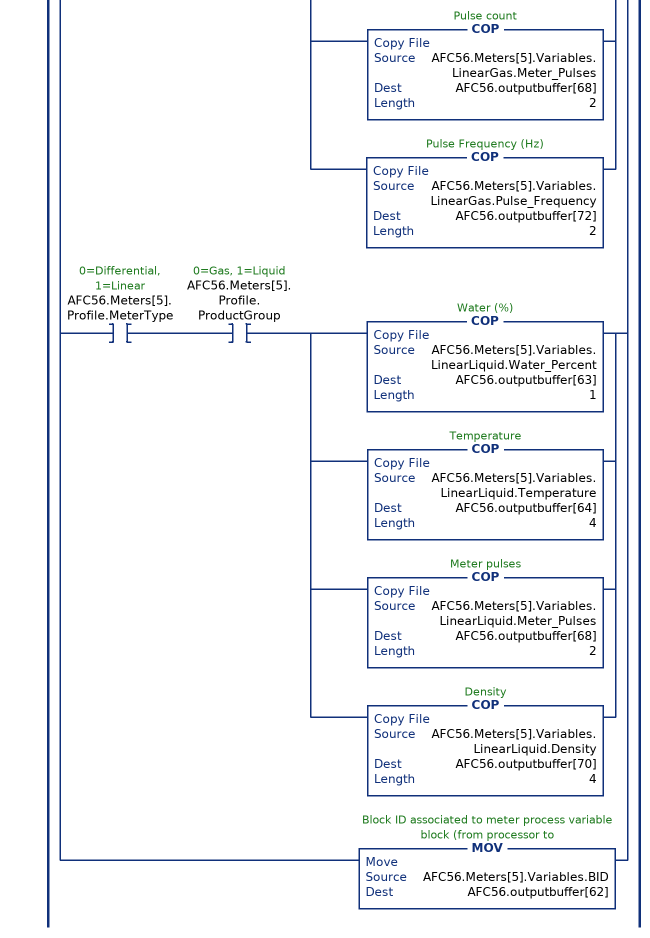
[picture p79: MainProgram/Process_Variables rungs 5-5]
   5: [ADD(6,8192,AFC56.Meters[5].Variables.BID) ,XIO(AFC56.EnableStatus.Meter6) [OTE(AFC56.Meters[5].Variables.BID.8) ,OTU(AFC56.DisableMeter.Meter6) ] ,XIC(AFC56.EnableStatus.Meter6) OTU(AFC56.EnableMeter.Meter6) ,XIO(AFC56.Meters[5].Profile.MeterType) XIO(AFC56.Meters[5].Profile.ProductGroup) COP(AFC56.Meters[5].Variables.DifferentialGas.Temperature,AFC56.outputbuffer[64],6) ,XIO(AFC56.Meters[5].Profile.MeterType) XIC(AFC56.Meters[5].Profile.ProductGroup) [COP(AFC56.Meters[5].Variables.DifferentialLiquid.Water_Percent,AFC56.outputbuffer[63],1) ,COP(AFC56.Meters[5].Variables.DifferentialLiquid.Temperature,AFC56.outputbuffer[64],8) ] ,XIC(AFC56.Meters[5].Profile.MeterType) XIO(AFC56.Meters[5].Profile.ProductGroup) [COP(AFC56.Meters[5].Variables.LinearGas.Temperature,AFC56.outputbuffer[64],4) ,COP(AFC56.Meters[5].Variables.LinearGas.Meter_Pulses,AFC56.outputbuffer[68],2) ,COP(AFC56.Meters[5].Variables.LinearGas.Pulse_Frequency,AFC56.outputbuffer[72],2) ] ,XIC(AFC56.Meters[5].Profile.MeterType) XIC(AFC56.Meters[5].Profile.ProductGroup) [COP(AFC56.Meters[5].Variables.LinearLiquid.Water_Percent,AFC56.outputbuffer[63],1) ,COP(AFC56.Meters[5].Variables.LinearLiquid.Temperature,AFC56.outputbuffer[64],4) ,COP(AFC56.Meters[5].Variables.LinearLiquid.Meter_Pulses,AFC56.outputbuffer[68],2) ,COP(AFC56.Meters[5].Variables.LinearLiquid.Density,AFC56.outputbuffer[70],4) ] ,MOV(AFC56.Meters[5].Variables.BID,AFC56.outputbuffer[62]) ];
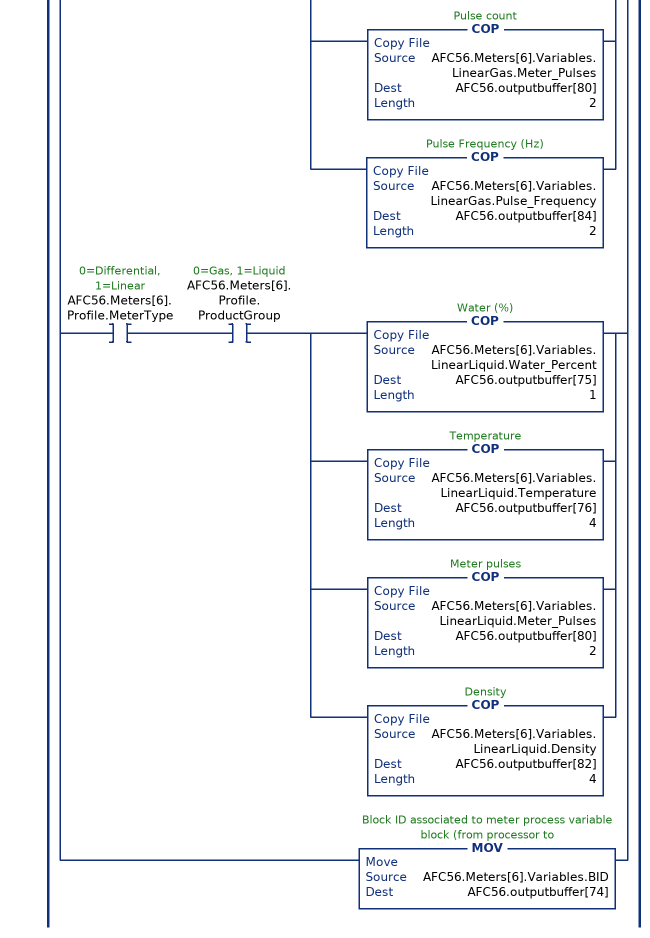
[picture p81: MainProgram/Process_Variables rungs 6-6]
   6: [ADD(7,8192,AFC56.Meters[6].Variables.BID) ,XIO(AFC56.EnableStatus.Meter7) [OTE(AFC56.Meters[6].Variables.BID.8) ,OTU(AFC56.DisableMeter.Meter7) ] ,XIC(AFC56.EnableStatus.Meter7) OTU(AFC56.EnableMeter.Meter7) ,XIO(AFC56.Meters[6].Profile.MeterType) XIO(AFC56.Meters[6].Profile.ProductGroup) COP(AFC56.Meters[6].Variables.DifferentialGas.Temperature,AFC56.outputbuffer[76],6) ,XIO(AFC56.Meters[6].Profile.MeterType) XIC(AFC56.Meters[6].Profile.ProductGroup) [COP(AFC56.Meters[6].Variables.DifferentialLiquid.Water_Percent,AFC56.outputbuffer[75],1) ,COP(AFC56.Meters[6].Variables.DifferentialLiquid.Temperature,AFC56.outputbuffer[76],8) ] ,XIC(AFC56.Meters[6].Profile.MeterType) XIO(AFC56.Meters[6].Profile.ProductGroup) [COP(AFC56.Meters[6].Variables.LinearGas.Temperature,AFC56.outputbuffer[76],4) ,COP(AFC56.Meters[6].Variables.LinearGas.Meter_Pulses,AFC56.outputbuffer[80],2) ,COP(AFC56.Meters[6].Variables.LinearGas.Pulse_Frequency,AFC56.outputbuffer[84],2) ] ,XIC(AFC56.Meters[6].Profile.MeterType) XIC(AFC56.Meters[6].Profile.ProductGroup) [COP(AFC56.Meters[6].Variables.LinearLiquid.Water_Percent,AFC56.outputbuffer[75],1) ,COP(AFC56.Meters[6].Variables.LinearLiquid.Temperature,AFC56.outputbuffer[76],4) ,COP(AFC56.Meters[6].Variables.LinearLiquid.Meter_Pulses,AFC56.outputbuffer[80],2) ,COP(AFC56.Meters[6].Variables.LinearLiquid.Density,AFC56.outputbuffer[82],4) ] ,MOV(AFC56.Meters[6].Variables.BID,AFC56.outputbuffer[74]) ];
